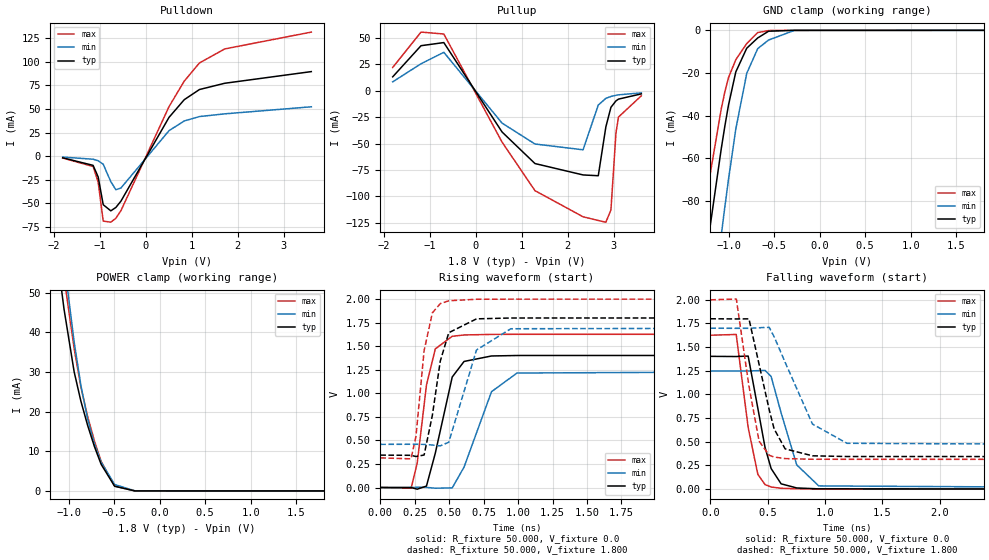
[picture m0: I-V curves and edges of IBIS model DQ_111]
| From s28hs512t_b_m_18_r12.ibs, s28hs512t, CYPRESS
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|   Model DQ_111
[Model] DQ_111
Model_type I/O
Polarity   Non-Inverting
Enable   Active-High
Vinl =  0.630V
Vinh =  1.170V
|Ac timing Thresholds
Vmeas =  0.900V
Cref =  15.000pF
C_comp   5.334pF   5.23pF   5.767pF
[Temperature Range]   25.000   0.125k   -40.000
[Voltage Range]   1.800V   1.700V   2.000V
[Pullup Reference]   1.800V   1.700V   2.000V
[Pulldown Reference]   0.0V   0.0V   0.0V
[POWER Clamp Reference]   1.800V   1.700V   2.000V
[GND Clamp Reference]   0.0V   0.0V   0.0V
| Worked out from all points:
|   slope of the pulldown table from 0 to 0.27 V, typ, clamps not added: 11.6 ohm
|   slope of the pullup table from 0 to 0.27 V, typ, clamps not added: 13.8 ohm
|   GND clamp passes 1 mA (typ) near -0.59 V on its own axis
|   POWER clamp passes 1 mA (typ) near -0.48 V on its own axis
|   rising waveform, R_fixture 50.000, V_fixture 0.0: 20-80 % time 121ps typ, 185ps min, 88ps max; typ from 0 V to 1.4 V
|   rising waveform, R_fixture 50.000, V_fixture 1.800: 20-80 % time 96.7ps typ, 139ps min, 72.4ps max; typ from 0.344 V to 1.8 V
|   falling waveform, R_fixture 50.000, V_fixture 0.0: 20-80 % time 134ps typ, 180ps min, 112ps max; typ from 1.4 V to 0 V
|   falling waveform, R_fixture 50.000, V_fixture 1.800: 20-80 % time 166ps typ, 271ps min, 127ps max; typ from 1.8 V to 0.344 V
[Pulldown]
|Voltage   I(typ)   I(min)   I(max)
-1.8V     -1.748mA   -952.4uA   -1.95mA
-1.14V    -9.709mA   -3.217mA   -10.93mA
-1.03V    -21.94mA   -4.831mA   -27.4mA
-920mV    -51.37mA   -8.556mA   -68.7mA
-755mV    -57.85mA   -26.98mA   -69.85mA
-645mV    -54.23mA   -35.5mA    -65.68mA
-535mV    -47.54mA   -33.65mA   -57.65mA
510mV     41.13mA    27.03mA    52.49mA
840mV     59.78mA    37.28mA    79.41mA
1.17V     70.52mA    41.91mA    98.67mA
1.72V     77.16mA    44.79mA    113.5mA
3.6V      89.49mA    52.26mA    131.3mA
[Pullup]
|Voltage   I(typ)   I(min)   I(max)
-1.8V     13.04mA    8.295mA    21.9mA
-1.185V   42.45mA    25.39mA    55.31mA
-690mV    45.4mA     36.22mA    53.5mA
575mV     -39.07mA   -30.69mA   -48.65mA
1.29V     -68.9mA    -50.42mA   -94.51mA
2.335V    -79.66mA   -55.9mA    -119.2mA
2.665V    -80.41mA   -13.62mA   -122.7mA
2.83V     -34.23mA   -7.312mA   -124.3mA
2.94V     -15.78mA   -5.491mA   -112.7mA
3.05V     -9.639mA   -4.372mA   -39.68mA
3.105V    -8.005mA   -3.963mA   -24.92mA
3.6V      -3.072mA   -2.128mA   -4.894mA
[GND_clamp]
|Voltage   I(typ)   I(min)   I(max)
-1.8V     -294mA     -373mA     -247.3mA
-1.28V    -116.8mA   -168.5mA   -89.46mA
-1.2V     -91.34mA   -138.7mA   -67.04mA
-1.08V    -55.6mA    -96.11mA   -36.91mA
-1.04V    -44.83mA   -82.66mA   -28.74mA
-1V       -34.98mA   -69.76mA   -22.14mA
-920mV    -19.48mA   -46.23mA   -13.73mA
-800mV    -8.377mA   -20.18mA   -6.205mA
-680mV    -3.579mA   -8.59mA    -1.029mA
-560mV    -408.3uA   -4.544mA   -113.8uA
-280mV    -162.8nA   -73.51uA   -82.13nA
1.8V      272.8pA    325nA      188.3pA
[POWER_clamp]
|Voltage   I(typ)   I(min)   I(max)
-1.8V     236.7mA    239.1mA    251.1mA
-1.123V   59.68mA    73.25mA    67.66mA
-1.086V   52.46mA    65.42mA    60.6mA
-1.049V   45.83mA    57.89mA    53.9mA
-938mV    30.03mA    37.57mA    35.87mA
-864mV    22.62mA    26.6mA     26.18mA
-790mV    16.52mA    18.14mA    18.76mA
-716mV    11.21mA    11.92mA    12.63mA
-642mV    6.708mA    7.258mA    7.47mA
-494mV    1.178mA    1.619mA    1.205mA
-272mV    6.291uA    28.11uA    4.439uA
1.8V      0A         0A         0A
[Ramp]
| variable   typ   min   max
dV/dt_r   0.842/0.121n   0.749/0.184n   0.976/88.095p
dV/dt_f   0.874/0.166n   0.745/0.270n   1.011/0.127n
R_load = 50.000
[Rising Waveform]
R_fixture= 50.000
V_fixture= 0.0
V_fixture_min= 0.0
V_fixture_max= 0.0
|time   V(typ)   V(min)   V(max)
0s        3.14uV     3.708uV    4.86uV
224ps     -850.6uV   1.26mV     -7.111mV
268ps     -17.58mV   2.006mV    259.7mV
335ps     15.32mV    1.627mV    1.086V
399ps     363.3mV    -7.319mV   1.471V
522ps     1.173V     -4.043mV   1.605V
608ps     1.338V     217.5mV    1.619V
807ps     1.396V     1.017V     1.625V
992ps     1.401V     1.215V     1.626V
6ns       1.403V     1.249V     1.626V
[Rising Waveform]
R_fixture= 50.000
V_fixture= 1.800
V_fixture_min= 1.700
V_fixture_max= 2.000
|time   V(typ)   V(min)   V(max)
0s        343.7mV    457.9mV    314.6mV
223ps     341.8mV    459mV      304.2mV
259ps     329mV      459mV      544.7mV
318ps     345mV      457.7mV    1.453V
378ps     767.3mV    450.9mV    1.854V
435ps     1.34V      442.1mV    1.951V
497ps     1.643V     480.8mV    1.982V
698ps     1.79V      1.459V     1.998V
947ps     1.799V     1.685V     1.999V
6ns       1.8V       1.7V       2V
[Falling Waveform]
R_fixture= 50.000
V_fixture= 0.0
V_fixture_min= 0.0
V_fixture_max= 0.0
|time   V(typ)   V(min)   V(max)
0s        1.403V     1.248V     1.626V
226ps     1.401V     1.248V     1.634V
330ps     1.406V     1.248V     651.5mV
414ps     856.2mV    1.252V     157.3mV
477ps     441.2mV    1.255V     48.19mV
530ps     218mV      1.19V      22.82mV
617ps     56.38mV    806.1mV    9.42mV
753ps     12.87mV    256.2mV    4.186mV
945ps     3.193mV    34.48mV    2.367mV
6ns       1.518uV    10.85uV    -870.1nV
[Falling Waveform]
R_fixture= 50.000
V_fixture= 1.800
V_fixture_min= 1.700
V_fixture_max= 2.000
|time   V(typ)   V(min)   V(max)
0s        1.8V       1.7V       2V
227ps     1.798V     1.699V     2.008V
337ps     1.799V     1.699V     1.088V
425ps     1.319V     1.705V     507.2mV
513ps     840.6mV    1.71V      358.4mV
556ps     637mV      1.61V      339.4mV
652ps     425.7mV    1.34V      323mV
890ps     352.3mV    687.6mV    316mV
1.191ns   344.8mV    484.5mV    315.3mV
6ns       343.7mV    457.9mV    314.6mV
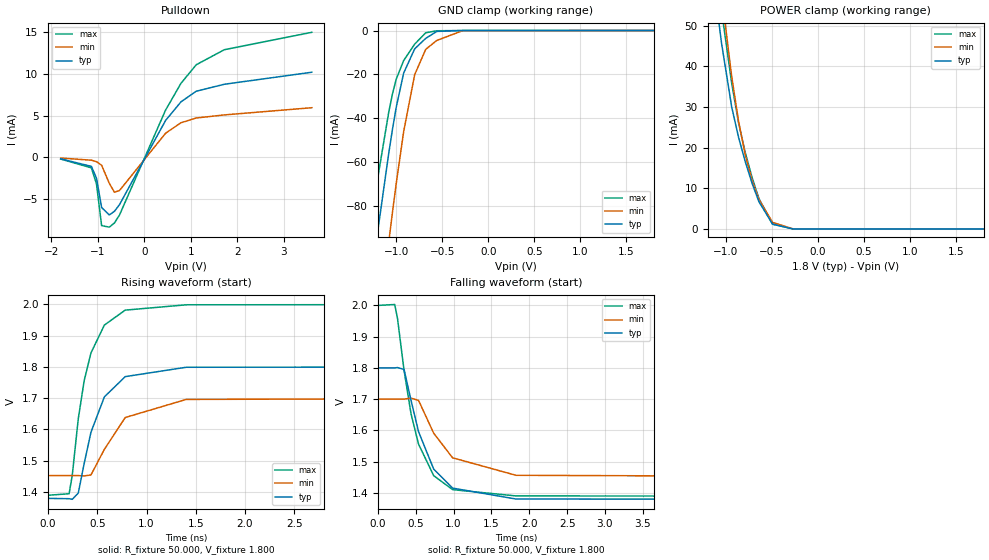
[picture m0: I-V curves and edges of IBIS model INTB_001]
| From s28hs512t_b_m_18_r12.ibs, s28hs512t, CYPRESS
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|   Model INTB_001
[Model] INTB_001
Model_type Open_drain
Polarity   Inverting
Enable   Active-High
Vmeas =  0.900V
Cref =   15.0000pF
Rref =   6.2000k
Vref =   1.8000V
C_comp   5.334pF   5.23pF   5.767pF
[Temperature Range]   25.000   0.125k   -40.000
[Voltage Range]   1.800V   1.700V   2.000V
[Pullup Reference]   1.800V   1.700V   2.000V
[Pulldown Reference]   0.0V   0.0V   0.0V
[POWER Clamp Reference]   1.800V   1.700V   2.000V
[GND Clamp Reference]   0.0V   0.0V   0.0V
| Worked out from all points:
|   slope of the pulldown table from 0 to 0.27 V, typ, clamps not added: 97.3 ohm
|   GND clamp passes 1 mA (typ) near -0.59 V on its own axis
|   POWER clamp passes 1 mA (typ) near -0.48 V on its own axis
|   rising waveform, R_fixture 50.000, V_fixture 1.800: 20-80 % time 245ps typ, 307ps min, 209ps max; typ from 1.38 V to 1.8 V
|   falling waveform, R_fixture 50.000, V_fixture 1.800: 20-80 % time 353ps typ, 421ps min, 303ps max; typ from 1.8 V to 1.38 V
[Pulldown]
|Voltage   I(typ)   I(min)   I(max)
-1.8V     -195.3uA   -105uA     -226.1uA
-1.14V    -1.107mA   -359.3uA   -1.282mA
-1.03V    -2.53mA    -542.5uA   -3.238mA
-920mV    -6.053mA   -969uA     -8.231mA
-755mV    -6.944mA   -3.143mA   -8.415mA
-645mV    -6.511mA   -4.216mA   -7.917mA
-535mV    -5.702mA   -4.004mA   -6.947mA
455mV     4.411mA    2.881mA    5.658mA
785mV     6.651mA    4.138mA    8.875mA
1.115V    7.935mA    4.717mA    11.12mA
1.72V     8.774mA    5.086mA    12.93mA
3.6V      10.22mA    5.952mA    15.02mA
[GND_clamp]
|Voltage   I(typ)   I(min)   I(max)
-1.8V     -294mA     -373mA     -247.3mA
-1.28V    -116.8mA   -168.5mA   -89.46mA
-1.2V     -91.34mA   -138.7mA   -67.04mA
-1.08V    -55.6mA    -96.11mA   -36.91mA
-1.04V    -44.83mA   -82.66mA   -28.74mA
-1V       -34.98mA   -69.76mA   -22.14mA
-920mV    -19.48mA   -46.23mA   -13.73mA
-800mV    -8.377mA   -20.18mA   -6.205mA
-680mV    -3.579mA   -8.59mA    -1.029mA
-560mV    -408.3uA   -4.544mA   -113.8uA
-280mV    -162.8nA   -73.51uA   -82.13nA
1.8V      272.8pA    325nA      188.3pA
[POWER_clamp]
|Voltage   I(typ)   I(min)   I(max)
-1.8V     236.7mA    239.1mA    251.1mA
-1.123V   59.68mA    73.25mA    67.66mA
-1.086V   52.46mA    65.42mA    60.6mA
-1.049V   45.83mA    57.89mA    53.9mA
-938mV    30.03mA    37.57mA    35.87mA
-864mV    22.62mA    26.6mA     26.18mA
-790mV    16.52mA    18.14mA    18.76mA
-716mV    11.21mA    11.92mA    12.63mA
-642mV    6.708mA    7.258mA    7.47mA
-494mV    1.178mA    1.619mA    1.205mA
-272mV    6.291uA    28.11uA    4.439uA
1.8V      0A         0A         0A
[Ramp]
| variable   typ   min   max
dV/dt_r   0.260/0.379n   0.189/0.444n   0.369/0.324n
dV/dt_f   0.253/0.353n   0.149/0.420n   0.367/0.303n
R_load = 50.000
[Rising Waveform]
R_fixture= 50.000
V_fixture= 1.800
V_fixture_min= 1.700
V_fixture_max= 2.000
|time   V(typ)   V(min)   V(max)
0s        1.379V     1.452V     1.389V
213ps     1.378V     1.452V     1.394V
245ps     1.376V     1.452V     1.453V
306ps     1.396V     1.452V     1.634V
366ps     1.491V     1.451V     1.756V
435ps     1.591V     1.454V     1.845V
571ps     1.704V     1.536V     1.934V
783ps     1.769V     1.638V     1.982V
1.403ns   1.799V     1.696V     1.999V
6ns       1.8V       1.7V       2V
[Falling Waveform]
R_fixture= 50.000
V_fixture= 1.800
V_fixture_min= 1.700
V_fixture_max= 2.000
|time   V(typ)   V(min)   V(max)
0s        1.8V       1.7V       2V
223ps     1.8V       1.7V       2.003V
259ps     1.801V     1.7V       1.959V
346ps     1.795V     1.7V       1.792V
438ps     1.696V     1.703V     1.653V
537ps     1.596V     1.696V     1.556V
737ps     1.476V     1.591V     1.455V
987ps     1.415V     1.512V     1.41V
1.824ns   1.38V      1.456V     1.39V
6ns       1.379V     1.452V     1.389V
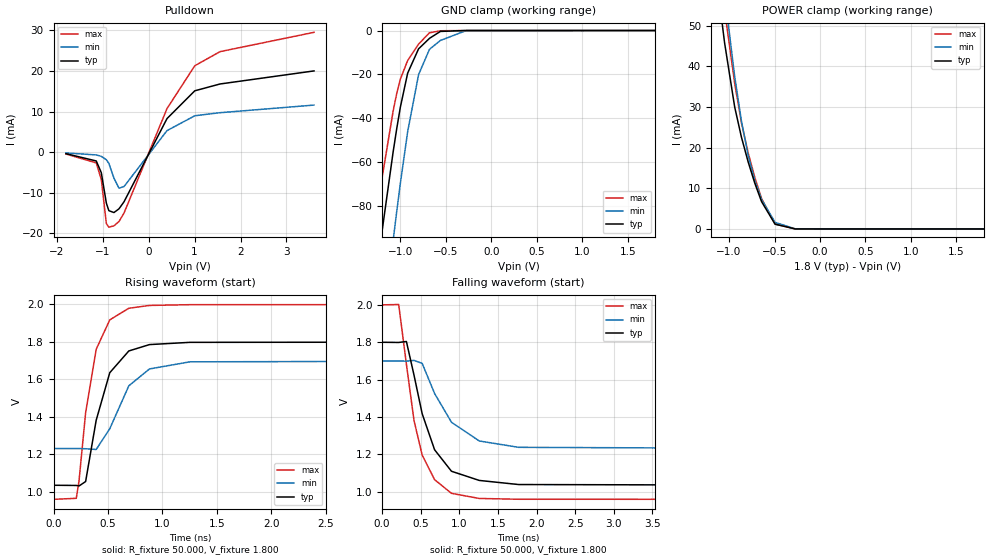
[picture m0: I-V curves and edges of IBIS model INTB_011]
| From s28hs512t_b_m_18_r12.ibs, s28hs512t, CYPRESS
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|   Model INTB_011
[Model] INTB_011
Model_type Open_drain
Polarity   Inverting
Enable   Active-High
Vmeas =  0.900V
Cref =   15.0000pF
Rref =   6.2000k
Vref =   1.8000V
C_comp   5.334pF   5.23pF   5.767pF
[Temperature Range]   25.000   0.125k   -40.000
[Voltage Range]   1.800V   1.700V   2.000V
[Pullup Reference]   1.800V   1.700V   2.000V
[Pulldown Reference]   0.0V   0.0V   0.0V
[POWER Clamp Reference]   1.800V   1.700V   2.000V
[GND Clamp Reference]   0.0V   0.0V   0.0V
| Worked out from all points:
|   slope of the pulldown table from 0 to 0.27 V, typ, clamps not added: 46 ohm
|   GND clamp passes 1 mA (typ) near -0.59 V on its own axis
|   POWER clamp passes 1 mA (typ) near -0.48 V on its own axis
|   rising waveform, R_fixture 50.000, V_fixture 1.800: 20-80 % time 189ps typ, 242ps min, 155ps max; typ from 1.03 V to 1.8 V
|   falling waveform, R_fixture 50.000, V_fixture 1.800: 20-80 % time 325ps typ, 416ps min, 264ps max; typ from 1.8 V to 1.03 V
[Pulldown]
|Voltage   I(typ)   I(min)   I(max)
-1.8V     -366.9uA   -191.9uA   -456.2uA
-1.14V    -2.167mA   -674.6uA   -2.645mA
-1.03V    -5.057mA   -1.029mA   -6.763mA
-920mV    -12.57mA   -1.87mA    -17.6mA
-865mV    -14.42mA   -2.78mA    -18.48mA
-755mV    -14.88mA   -6.399mA   -18.15mA
-645mV    -13.96mA   -8.877mA   -17.09mA
-535mV    -12.21mA   -8.462mA   -14.99mA
400mV     8.281mA    5.315mA    10.75mA
1.005V    15.13mA    8.975mA    21.31mA
1.555V    16.81mA    9.731mA    24.78mA
3.6V      20.03mA    11.61mA    29.54mA
[GND_clamp]
|Voltage   I(typ)   I(min)   I(max)
-1.8V     -294mA     -373mA     -247.3mA
-1.28V    -116.8mA   -168.5mA   -89.46mA
-1.2V     -91.34mA   -138.7mA   -67.04mA
-1.08V    -55.6mA    -96.11mA   -36.91mA
-1.04V    -44.83mA   -82.66mA   -28.74mA
-1V       -34.98mA   -69.76mA   -22.14mA
-920mV    -19.48mA   -46.23mA   -13.73mA
-800mV    -8.377mA   -20.18mA   -6.205mA
-680mV    -3.579mA   -8.59mA    -1.029mA
-560mV    -408.3uA   -4.544mA   -113.8uA
-280mV    -162.8nA   -73.51uA   -82.13nA
1.8V      272.8pA    325nA      188.3pA
[POWER_clamp]
|Voltage   I(typ)   I(min)   I(max)
-1.8V     236.7mA    239.1mA    251.1mA
-1.123V   59.68mA    73.25mA    67.66mA
-1.086V   52.46mA    65.42mA    60.6mA
-1.049V   45.83mA    57.89mA    53.9mA
-938mV    30.03mA    37.57mA    35.87mA
-864mV    22.62mA    26.6mA     26.18mA
-790mV    16.52mA    18.14mA    18.76mA
-716mV    11.21mA    11.92mA    12.63mA
-642mV    6.708mA    7.258mA    7.47mA
-494mV    1.178mA    1.619mA    1.205mA
-272mV    6.291uA    28.11uA    4.439uA
1.8V      0A         0A         0A
[Ramp]
| variable   typ   min   max
dV/dt_r   0.456/0.325n   0.345/0.410n   0.604/0.250n
dV/dt_f   0.459/0.325n   0.281/0.416n   0.624/0.264n
R_load = 50.000
[Rising Waveform]
R_fixture= 50.000
V_fixture= 1.800
V_fixture_min= 1.700
V_fixture_max= 2.000
|time   V(typ)   V(min)   V(max)
0s        1.035V     1.231V     959.9mV
209ps     1.034V     1.231V     965.3mV
234ps     1.031V     1.231V     1.057V
295ps     1.055V     1.23V      1.422V
392ps     1.382V     1.226V     1.761V
517ps     1.636V     1.337V     1.918V
692ps     1.752V     1.566V     1.98V
882ps     1.786V     1.656V     1.995V
1.254ns   1.798V     1.694V     1.999V
6ns       1.8V       1.7V       2V
[Falling Waveform]
R_fixture= 50.000
V_fixture= 1.800
V_fixture_min= 1.700
V_fixture_max= 2.000
|time   V(typ)   V(min)   V(max)
0s        1.8V       1.7V       2V
214ps     1.799V     1.7V       2.002V
314ps     1.804V     1.699V     1.682V
413ps     1.623V     1.703V     1.38V
518ps     1.418V     1.687V     1.197V
679ps     1.225V     1.526V     1.065V
898ps     1.11V      1.372V     991.9mV
1.258ns   1.061V     1.272V     964.6mV
1.768ns   1.039V     1.238V     960.3mV
6ns       1.035V     1.231V     959.9mV
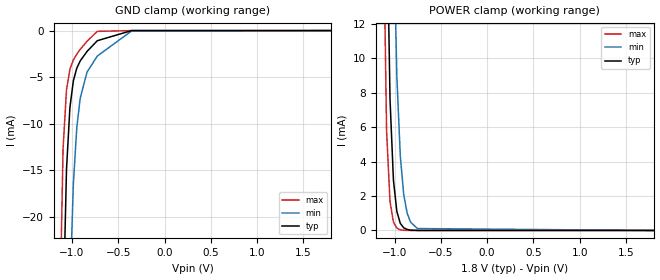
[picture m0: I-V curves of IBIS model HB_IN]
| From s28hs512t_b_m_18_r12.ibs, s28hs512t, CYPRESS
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|   Model HB_IN
[Model] HB_IN
Model_type Input
Vinl =  0.630V
Vinh =  1.170V
C_comp   1.57pF   1.561pF   1.597pF
[Temperature Range]   25.000   0.125k   -40.000
[Voltage Range]   1.800V   1.700V   2.000V
[POWER Clamp Reference]   1.800V   1.700V   2.000V
[GND Clamp Reference]   0.0V   0.0V   0.0V
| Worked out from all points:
|   GND clamp passes 1 mA (typ) near -0.72 V on its own axis
|   POWER clamp passes 1 mA (typ) near -0.97 V on its own axis
[GND_clamp]
|Voltage   I(typ)   I(min)   I(max)
-1.8V     -3.976A    -3.996A    -4.02A
-1.134V   -66.02mA   -153.1mA   -31.63mA
-1.097V   -30.77mA   -89.27mA   -12.72mA
-1.06V    -14.94mA   -50.14mA   -6.374mA
-1.023V   -8.261mA   -28.17mA   -4.149mA
-986mV    -5.404mA   -16.51mA   -3.158mA
-949mV    -4.044mA   -10.45mA   -2.533mA
-912mV    -3.261mA   -7.271mA   -2.025mA
-838mV    -2.238mA   -4.455mA   -1.141mA
-727mV    -1.087mA   -2.735mA   -84.29uA
-357mV    -101.6nA   -43.79uA   -4.822nA
1.8V      0A         0A         0A
[POWER_clamp]
|Voltage   I(typ)   I(min)   I(max)
-1.8V     3.965A     3.984A     4.008A
-1.123V   47.25mA    124.3mA    19.07mA
-1.086V   19.53mA    68.91mA    5.781mA
-1.049V   7.643mA    36.04mA    1.683mA
-1.012V   2.918mA    18.14mA    483.4uA
-975mV    1.103mA    8.921mA    138.3uA
-938mV    415uA      4.336mA    39.54uA
-901mV    155.9uA    2.095mA    11.3uA
-864mV    58.57uA    1.009mA    3.228uA
-827mV    21.99uA    485uA      922.3nA
-753mV    3.101uA    112uA      75.42nA
1.8V      0A         0A         0A
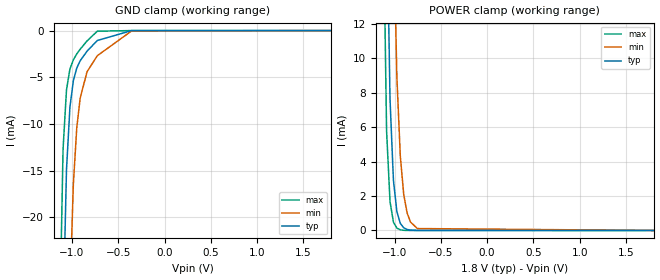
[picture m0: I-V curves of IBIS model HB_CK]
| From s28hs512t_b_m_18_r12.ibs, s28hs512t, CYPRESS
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|   Model HB_CK
[Model] HB_CK
Model_type Input
Vinl =  0.630V
Vinh =  1.170V
C_comp   1.861pF   1.791pF   1.942pF
[Temperature Range]   25.000   0.125k   -40.000
[Voltage Range]   1.800V   1.700V   2.000V
[POWER Clamp Reference]   1.800V   1.700V   2.000V
[GND Clamp Reference]   0.0V   0.0V   0.0V
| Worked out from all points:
|   GND clamp passes 1 mA (typ) near -0.72 V on its own axis
|   POWER clamp passes 1 mA (typ) near -0.97 V on its own axis
[GND_clamp]
|Voltage   I(typ)   I(min)   I(max)
-1.8V     -3.976A    -3.996A    -4.02A
-1.134V   -65.99mA   -153mA     -31.61mA
-1.097V   -30.74mA   -89.22mA   -12.68mA
-1.06V    -14.9mA    -50.09mA   -6.347mA
-1.023V   -8.228mA   -28.12mA   -4.121mA
-986mV    -5.37mA    -16.46mA   -3.129mA
-949mV    -4.01mA    -10.41mA   -2.503mA
-912mV    -3.227mA   -7.221mA   -1.994mA
-838mV    -2.205mA   -4.407mA   -1.11mA
-727mV    -1.063mA   -2.69mA    -65.47uA
-357mV    -15.18nA   -41.88uA   -47.29pA
1.8V      0A         0A         0A
[POWER_clamp]
|Voltage   I(typ)   I(min)   I(max)
-1.8V     3.965A     3.984A     4.008A
-1.123V   47.25mA    124.3mA    19.07mA
-1.086V   19.53mA    68.91mA    5.781mA
-1.049V   7.643mA    36.04mA    1.683mA
-1.012V   2.918mA    18.14mA    483.4uA
-975mV    1.103mA    8.921mA    138.3uA
-938mV    415uA      4.336mA    39.54uA
-901mV    155.9uA    2.095mA    11.3uA
-864mV    58.56uA    1.009mA    3.228uA
-827mV    21.99uA    485uA      922.3nA
-753mV    3.1uA      111.9uA    75.37nA
1.8V      0A         0A         0A
